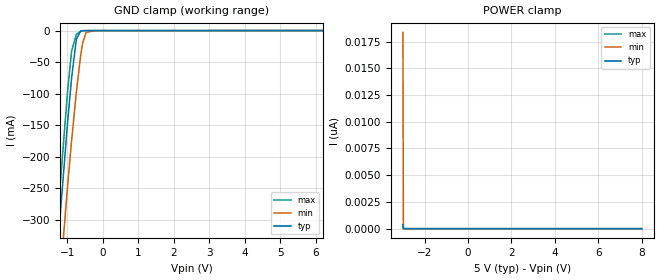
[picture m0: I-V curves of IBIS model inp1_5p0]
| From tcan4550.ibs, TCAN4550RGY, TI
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|   inp1_5p0 Model
[Model]   inp1_5p0
Model_type   Input
Vinl = 1.5
Vinh = 3.5
|   typ   min   max
C_comp   4.717pF   4.443pF   4.894pF
|  Where Nom  PVT is Nominal Process, 5V,   27C
|   Fast PVT is Strong Process,  5.25, -40C
|   Slow PVT is Weak Process,   4.75V, 150C
[Model spec]
|subparameter
Vinl   1.5   1.425   1.575
Vinh   3.5   3.325   3.675
[Voltage Range]   5   4.75   5.25
|Junction Temperature
[Temperature Range]   27   150   -40
[Power Clamp Reference]   5   4.75   5.25
[GND Clamp Reference]   0   0   0
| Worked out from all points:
|   GND clamp passes 1 mA (typ) near -0.63 V on its own axis
[GND Clamp]
|   Voltage   I(typ)   I(min)   I(max)
-3V       -1.774A    -1.806A    -1.769A
-1.526V   -547.9mA   -635.7mA   -506.4mA
-1.251V   -331.4mA   -428.8mA   -283.7mA
-1.218V   -306.4mA   -404.7mA   -258.2mA
-987mV    -143mA     -243.8mA   -93.65mA
-877mV    -74.98mA   -174.1mA   -32.25mA
-745mV    -14.11mA   -98.27mA   -6.274mA
-624mV    -794.5uA   -40.13mA   -894.3uA
-569mV    -217.7uA   -20.52mA   -257.7uA
-470mV    -33.98uA   -2.998mA   -37.08uA
-239mV    -18.51uA   -23.35uA   -22.76uA
8V        0A         0A         0A
[POWER Clamp]
|   Voltage   I(typ)   I(min)   I(max)
-3V       381.8pA    18.36nA    380.5pA
-2.978V   0A         0A         0A
-2.967V   0A         0A         0A
8V        0A         0A         0A
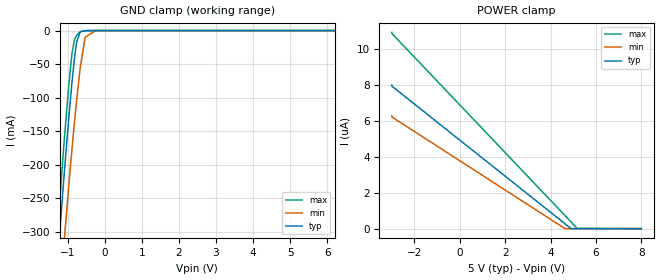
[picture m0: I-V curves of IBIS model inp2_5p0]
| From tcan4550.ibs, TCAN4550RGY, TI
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|   inp2_5p0 Model
[Model]   inp2_5p0
Model_type   Input
Vinl = 1.5
Vinh = 3.5
|   typ   min   max
C_comp   4.717pF   4.443pF   4.894pF
|  Where Nom  PVT is Nominal Process, 5V,   27C
|   Fast PVT is Strong Process,  5.25, -40C
|   Slow PVT is Weak Process,   4.75V, 150C
[Model spec]
|subparameter
Vinl   1.5   1.425   1.575
Vinh   3.5   3.325   3.675
[Voltage Range]   5   4.75   5.25
|Junction Temperature
[Temperature Range]   27   150   -40
[Power Clamp Reference]   5   4.75   5.25
[GND Clamp Reference]   0   0   0
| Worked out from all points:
|   GND clamp passes 1 mA (typ) near -0.63 V on its own axis
[GND Clamp]
|   Voltage   I(typ)   I(min)   I(max)
-3V       -1.774A    -1.806A    -1.769A
-1.35V    -407.9mA   -502.2mA   -362.1mA
-1.24V    -323mA     -420.7mA   -275.1mA
-1.097V   -218mA     -318.4mA   -168.5mA
-965mV    -128.8mA   -229.4mA   -79.78mA
-877mV    -74.98mA   -174.1mA   -32.25mA
-811mV    -39.84mA   -135mA     -13.29mA
-756mV    -17.43mA   -104.2mA   -7.114mA
-657mV    -1.761mA   -54.39mA   -1.703mA
-525mV    -65.42uA   -9.811mA   -72.23uA
-239mV    -137.8nA   -6.811uA   -213.8nA
8V        0A         0A         0A
[POWER Clamp]
|   Voltage   I(typ)   I(min)   I(max)
-3V       7.98uA     6.269uA    10.9uA
-2.989V   7.907uA    6.199uA    10.83uA
4.634V    277.2nA    2.624nA    731.9nA
4.898V    7.32nA     0A         379.5nA
5.173V    0A         0A         10.05nA
8V        0A         0A         0A
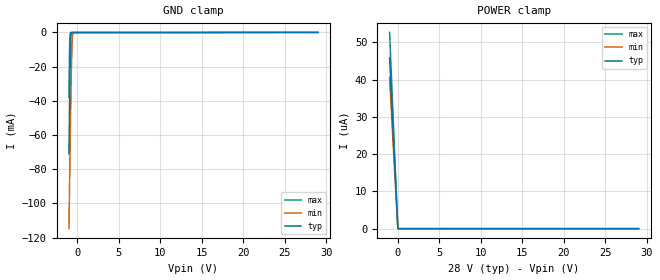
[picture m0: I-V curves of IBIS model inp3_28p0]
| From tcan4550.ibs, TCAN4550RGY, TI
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|   inp3_28p0 Model
[Model]   inp3_28p0
Model_type   Input
Vinl = 25
Vinh = 26
|   typ   min   max
C_comp   2.294pF   2.258pF   2.300pF
|  Where Nom  PVT is Nominal Process, 28V,   27C
|   Fast PVT is Strong Process,  26V, -40C
|   Slow PVT is Weak Process,   30V, 150C
[Model spec]
|subparameter
Vinl   25   23   27
Vinh   26   24   28
[Voltage Range]   28   26   30
|Junction Temperature
[Temperature Range]   27   150   -40
[Power Clamp Reference]   28   26   30
[GND Clamp Reference]   0   0   0
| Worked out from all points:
|   GND clamp passes 1 mA (typ) near -0.76 V on its own axis
[GND Clamp]
|   Voltage   I(typ)   I(min)   I(max)
-1V       -71.04mA   -114.8mA   -38.01mA
-940mV    -45.59mA   -93.27mA   -13.67mA
-910mV    -33.71mA   -82.69mA   -5.733mA
-880mV    -22.92mA   -72.29mA   -1.793mA
-850mV    -13.79mA   -62.13mA   -490.1uA
-820mV    -7.017mA   -52.27mA   -152.6uA
-790mV    -2.959mA   -42.82mA   -71.11uA
-730mV    -386.4uA   -25.67mA   -44.73uA
-640mV    -44.4uA    -7.393mA   -38.46uA
-580mV    -31.14uA   -2.071mA   -35.18uA
-490mV    -25.75uA   -223.3uA   -30.33uA
29V       0A         0A         0A
[POWER Clamp]
|   Voltage   I(typ)   I(min)   I(max)
-1V       45.82uA    40.47uA    52.66uA
-520mV    23.32uA    20.54uA    26.8uA
-100mV    4.244uA    3.751uA    4.87uA
-10mV     303.2nA    268.7nA    360.4nA
50mV      0A         0A         0A
29V       0A         0A         0A
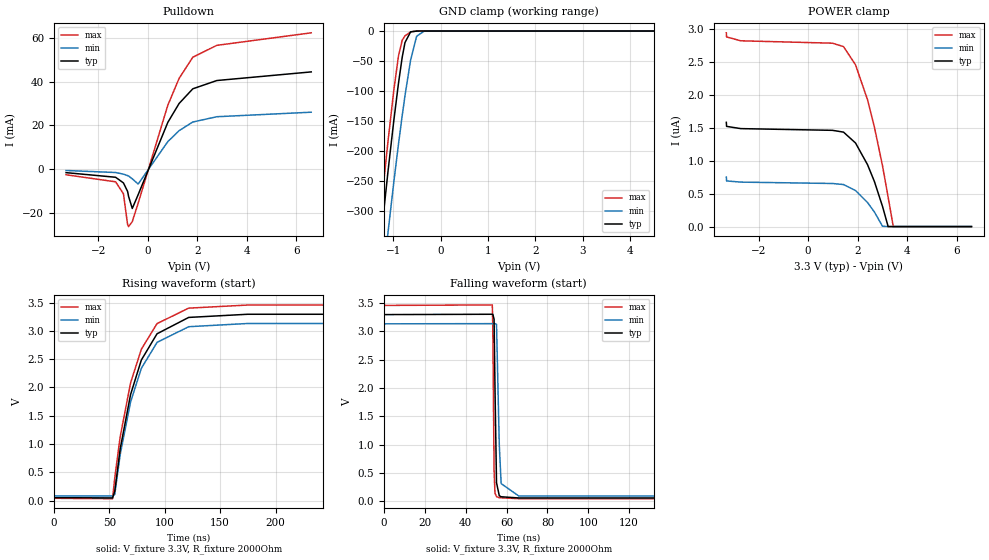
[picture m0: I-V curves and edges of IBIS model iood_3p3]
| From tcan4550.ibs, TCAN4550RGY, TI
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|   iood_3p3 Model
[Model]   iood_3p3
Model_type   I/O_open_drain
Polarity   Inverting
Enable   Active-High
Vinl = 0.99
Vinh = 2.31
Vmeas = 1.65
Vref = 3.3
Cref = 2pF
Rref = 2000
|   typ   min   max
C_comp   5.416pF   5.196pF   5.542pF
|  Where Nom  PVT is Nominal Process, 3.3V,   27C
|   Fast PVT is Strong Process,  3.465, -40C
|   Slow PVT is Weak Process,   3.135V, 150C
[Model spec]
|subparameter
Vinl   0.99   0.9405   1.0395
Vinh   2.31   2.1945   2.4255
[Voltage Range]   3.3   3.135   3.465
|Junction Temperature
[Temperature Range]   27   150   -40
[Pullup Reference]   3.3   3.135   3.465
[Pulldown Reference]   0   0   0
[Power Clamp Reference]   3.3   3.135   3.465
[GND Clamp Reference]   0   0   0
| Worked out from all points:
|   slope of the pulldown table from 0 to 0.495 V, typ, clamps not added: 35.6 ohm
|   GND clamp passes 1 mA (typ) near -0.62 V on its own axis
|   falling waveform, V_fixture 3.3V, R_fixture 2000Ohm: 20-80 % time 639ps typ, 1.06ns min, 470ps max; typ from 3.3 V to 0.053 V
|   rising waveform, V_fixture 3.3V, R_fixture 2000Ohm: 20-80 % time 24.4ns typ, 24.4ns min, 24.3ns max; typ from 0.053 V to 3.3 V
[Pulldown]
|   Voltage   I(typ)   I(min)   I(max)
-3.3V     -1.646mA   -663.5uA   -2.612mA
-1.3V     -3.761mA   -1.587mA   -5.841mA
-983.4mV  -6.351mA   -2.34mA    -11.31mA
-815.1mV  -10.26mA   -3.007mA   -25.49mA
-775.5mV  -12.54mA   -3.204mA   -26.33mA
-627mV    -18.04mA   -4.459mA   -24.06mA
-389.4mV  -11.73mA   -6.863mA   -15.61mA
808.5mV   21.35mA    12.55mA    29.21mA
1.264V    30mA       17.56mA    41.48mA
1.818V    36.72mA    21.53mA    51.17mA
2.788V    40.5mA     23.94mA    56.6mA
6.6V      44.45mA    26.01mA    62.33mA
[GND Clamp]
|   Voltage   I(typ)   I(min)   I(max)
-3.3V     -2.034A    -2.058A    -2.034A
-1.31V    -380.2mA   -477.5mA   -332.6mA
-1.251V   -334.5mA   -433.5mA   -285.9mA
-1.112V   -231.9mA   -333.7mA   -181.8mA
-993.3mV  -150.2mA   -252.6mA   -99.87mA
-894.3mV  -87.7mA    -189.1mA   -42.1mA
-815.1mV  -44.1mA    -141.4mA   -15.53mA
-755.7mV  -19.24mA   -107.8mA   -8.037mA
-636.9mV  -1.41mA    -48.49mA   -1.417mA
-508.2mV  -58.86uA   -8.59mA    -61.73uA
-349.8mV  -1.01uA    -208.4uA   -1.025uA
6.6V      0A         0A         0A
[POWER Clamp]
|   Voltage   I(typ)   I(min)   I(max)
-3.3V     1.58uA     751.3nA    2.937uA
-3.29V    1.519uA    691.9nA    2.875uA
-2.716V   1.485uA    674.2nA    2.816uA
986.7mV   1.459uA    653.3nA    2.78uA
1.432V    1.432uA    637.3nA    2.728uA
1.917V    1.267uA    546.3nA    2.452uA
2.402V    938.4nA    364.5nA    1.922uA
2.68V     682.9nA    221.1nA    1.507uA
3.006V    307.1nA    5.102nA    923.2nA
3.234V    548.8pA    0A         446.7nA
3.442V    0A         0A         0A
6.6V      0A         0A         0A
[Ramp]
R_load = 2000
|   typ   min   max
dV/dt_r   1.94618/2.44387e-08   1.82918/2.44445e-08   2.05049/2.4312e-08
dV/dt_f   1.94618/6.37173e-10   1.82918/1.06111e-09   2.05049/4.67593e-10
[Falling Waveform]
V_fixture = 3.3V
V_fixture_min = 3.135V
V_fixture_max = 3.465V
R_fixture = 2000Ohm
C_fixture = 0F
|   Time   V(typ)   V(min)   V(max)
0s        3.297V     3.134V     3.459V
53.03ns   3.303V     3.137V     3.468V
53.28ns   3.304V     3.137V     3.053V
53.9ns    3.214V     3.137V     545.6mV
54.34ns   2.004V     3.137V     138.2mV
55.09ns   324.7mV    3.124V     78.97mV
56.45ns   94.28mV    988.5mV    58.48mV
57.36ns   76.02mV    308.8mV    56.93mV
65.99ns   54.87mV    89.25mV    42.28mV
25us      53.31mV    84.92mV    41.81mV
[Rising Waveform]
V_fixture = 3.3V
V_fixture_min = 3.135V
V_fixture_max = 3.465V
R_fixture = 2000Ohm
C_fixture = 0F
|   Time   V(typ)   V(min)   V(max)
0s        53.31mV    84.92mV    41.81mV
52.97ns   48.32mV    83.65mV    34.96mV
54.95ns   168.9mV    110.2mV    403.2mV
59.86ns   916.1mV    815mV      1.131V
69.21ns   1.875V     1.743V     2.081V
78.92ns   2.485V     2.338V     2.675V
93.07ns   2.949V     2.797V     3.129V
121.6ns   3.238V     3.074V     3.402V
174.8ns   3.294V     3.131V     3.457V
25us      3.297V     3.134V     3.459V
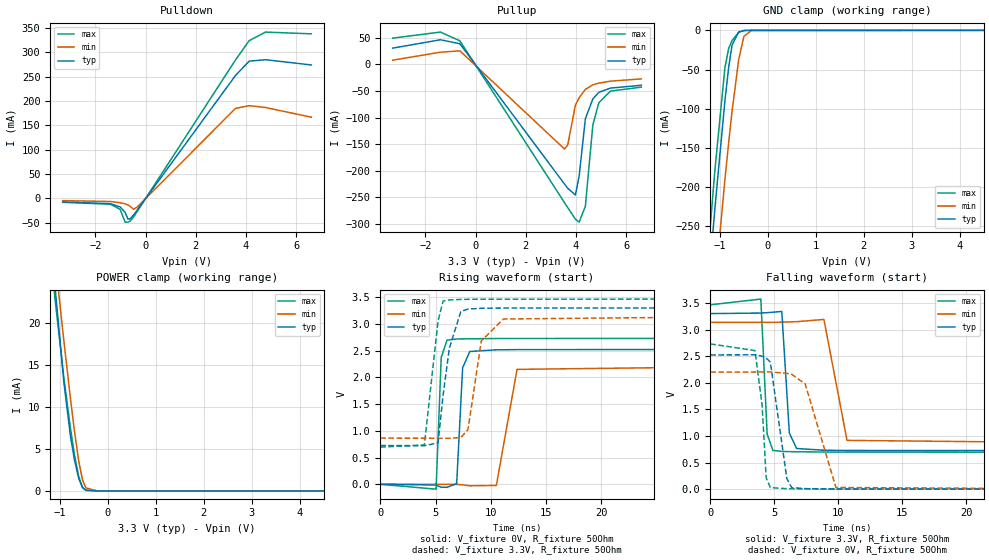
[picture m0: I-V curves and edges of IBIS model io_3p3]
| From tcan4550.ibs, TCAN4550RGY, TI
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|   io_3p3 Model
[Model]   io_3p3
Model_type   I/O
Polarity   Non-Inverting
Enable   Active-High
Vinl = 0.99
Vinh = 2.31
Vmeas = 1.65
Vref = 0
Cref = 2pF
Rref = 100000
|   typ   min   max
C_comp   9.675pF   8.583pF   10.03pF
|  Where Nom  PVT is Nominal Process, 3.3V,   27C
|   Fast PVT is Strong Process,  3.465, -40C
|   Slow PVT is Weak Process,   3.135V, 150C
[Model spec]
|subparameter
Vinl   0.99   0.9405   1.0395
Vinh   2.31   2.1945   2.4255
[Voltage Range]   3.3   3.135   3.465
|Junction Temperature
[Temperature Range]   27   150   -40
[Pullup Reference]   3.3   3.135   3.465
[Pulldown Reference]   0   0   0
[Power Clamp Reference]   3.3   3.135   3.465
[GND Clamp Reference]   0   0   0
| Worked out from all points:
|   slope of the pulldown table from 0 to 0.495 V, typ, clamps not added: 14.1 ohm
|   slope of the pullup table from 0 to 0.495 V, typ, clamps not added: 15.4 ohm
|   GND clamp passes 1 mA (typ) near -0.57 V on its own axis
|   POWER clamp passes 1 mA (typ) near -0.58 V on its own axis
|   falling waveform, V_fixture 3.3V, R_fixture 50Ohm: 20-80 % time 335ps typ, 504ps min, 257ps max; typ from 3.3 V to 0.724 V
|   rising waveform, V_fixture 0V, R_fixture 50Ohm: 20-80 % time 307ps typ, 501ps min, 221ps max; typ from 0 V to 2.52 V
|   rising waveform, V_fixture 3.3V, R_fixture 50Ohm: 20-80 % time 1.04ns typ, 1ns min, 953ps max; typ from 0.724 V to 3.3 V
|   falling waveform, V_fixture 0V, R_fixture 50Ohm: 20-80 % time 819ps typ, 1.35ns min, 508ps max; typ from 2.52 V to 0 V
[Pulldown]
|   Voltage   I(typ)   I(min)   I(max)
-3.3V     -7.321mA   -4.376mA   -7.77mA
-1.399V   -10.65mA   -6.17mA    -11.81mA
-1.013V   -17.43mA   -8.661mA   -22.41mA
-815.1mV  -28.61mA   -11.12mA   -48.5mA
-706.2mV  -41.98mA   -13.18mA   -48.68mA
-617.1mV  -41.78mA   -16.24mA   -46.47mA
-478.5mV  -33.95mA   -22.1mA    -38.04mA
-339.9mV  -24.21mA   -17.84mA   -27.11mA
3.58V     252.5mA    184.9mA    284.3mA
4.125V    281.9mA    190.6mA    324mA
4.778V    284.9mA    186.7mA    341.6mA
6.6V      274.1mA    166.9mA    338mA
[GND Clamp]
|   Voltage   I(typ)   I(min)   I(max)
-3.3V     -2.035A    -2.059A    -2.036A
-1.32V    -389.2mA   -485.8mA   -342.9mA
-1.251V   -335.9mA   -434.5mA   -288.4mA
-1.122V   -240.6mA   -341.7mA   -192mA
-1.092V   -219.5mA   -320.9mA   -170.8mA
-894.3mV  -89.68mA   -190.1mA   -47.42mA
-815.1mV  -46.35mA   -142.4mA   -22.67mA
-745.8mV  -18.8mA    -103.3mA   -13.02mA
-607.2mV  -2.033mA   -37.01mA   -2.543mA
-498.3mV  -237.2uA   -7.541mA   -248.7uA
-339.9mV  -14.59uA   -195.7uA   -15.4uA
6.6V      0A         0A         0A
[Pullup]
|   Voltage   I(typ)   I(min)   I(max)
-3.3V     30.66mA    7.971mA    49.52mA
-1.399V   46.39mA    22.94mA    60.85mA
-627mV    38.96mA    25.59mA    44.46mA
3.541V    -225.2mA   -159.3mA   -260.2mA
3.67V     -233.1mA   -151.6mA   -269.6mA
3.977V    -245.8mA   -76.26mA   -291.4mA
4.125V    -209.8mA   -62.46mA   -297mA
4.372V    -102.3mA   -47.06mA   -266.8mA
4.67V     -65mA      -38.41mA   -113.9mA
4.907V    -52.56mA   -35.12mA   -72.35mA
5.372V    -44.59mA   -31.58mA   -50.2mA
6.6V      -39.25mA   -27.21mA   -42.81mA
[POWER Clamp]
|   Voltage   I(typ)   I(min)   I(max)
-3.3V     185.2mA    152.1mA    196.5mA
-1.191V   30.4mA     32.54mA    28.48mA
-1.142V   27.04mA    29.85mA    25.32mA
-1.102V   24.4mA     27.71mA    22.96mA
-914.1mV  12.81mA    17.76mA    13.36mA
-775.5mV  6.381mA    10.82mA    7.329mA
-696.3mV  3.709mA    7.153mA    4.35mA
-607.2mV  1.498mA    3.57mA     1.717mA
-528mV    410.4uA    1.31mA     405.8uA
-458.7mV  84.75uA    360.7uA    61.26uA
-211.2mV  0A         963.1nA    0A
6.6V      0A         0A         0A
[Ramp]
R_load = 50
|   typ   min   max
dV/dt_r   1.51305/3.05831e-10   1.31974/4.99333e-10   1.63771/2.20599e-10
dV/dt_f   1.54536/3.33578e-10   1.36296/5.00669e-10   1.66199/2.55608e-10
[Falling Waveform]
V_fixture = 3.3V
V_fixture_min = 3.135V
V_fixture_max = 3.465V
R_fixture = 50Ohm
C_fixture = 0F
|   Time   V(typ)   V(min)   V(max)
0s        3.3V       3.135V     3.465V
3.953ns   3.31V      3.135V     3.573V
4.447ns   3.317V     3.135V     1.034V
4.893ns   3.326V     3.135V     729.6mV
5.59ns    3.34V      3.139V     709.4mV
6.182ns   1.054V     3.144V     705.3mV
6.751ns   764.5mV    3.148V     703.2mV
8.883ns   731.9mV    3.19V      697.7mV
10.69ns   727.5mV    917.2mV    697.5mV
33ns      724.4mV    863.4mV    695mV
[Rising Waveform]
V_fixture = 0V
V_fixture_min = 0V
V_fixture_max = 0V
R_fixture = 50Ohm
C_fixture = 0F
|   Time   V(typ)   V(min)   V(max)
0s        109.1uV    131.5uV    119.9uV
5.052ns   -13.65mV   283.3uV    -91.42mV
5.518ns   -55.33mV   297.3uV    2.374V
6.04ns    -57.27mV   313uV      2.696V
6.917ns   12.08mV    -2.397mV   2.718V
7.456ns   2.179V     -10.8mV    2.72V
8.107ns   2.484V     -28.63mV   2.722V
10.51ns   2.516V     -21.63mV   2.727V
12.38ns   2.519V     2.15V      2.727V
33ns      2.522V     2.2V       2.73V
[Rising Waveform]
V_fixture = 3.3V
V_fixture_min = 3.135V
V_fixture_max = 3.465V
R_fixture = 50Ohm
C_fixture = 0F
|   Time   V(typ)   V(min)   V(max)
0s        724.4mV    863.4mV    695mV
3.991ns   721.5mV    862mV      735.1mV
5.232ns   776mV      861.5mV    3.058V
5.692ns   1.677V     861.3mV    3.428V
6.256ns   2.546V     861.1mV    3.449V
7.296ns   3.233V     875mV      3.458V
7.942ns   3.277V     1.025V     3.46V
9.145ns   3.293V     2.682V     3.462V
11.15ns   3.297V     3.092V     3.462V
33ns      3.3V       3.135V     3.465V
[Falling Waveform]
|Gnd
V_fixture = 0V
V_fixture_min = 0V
V_fixture_max = 0V
R_fixture = 50Ohm
C_fixture = 0F
|   Time   V(typ)   V(min)   V(max)
0s        2.522V     2.2V       2.73V
3.494ns   2.526V     2.202V     2.605V
4.053ns   2.499V     2.203V     1.58V
4.37ns    2.465V     2.203V     215.5mV
4.695ns   2.388V     2.203V     29.02mV
5.988ns   196.1mV    2.177V     8.705mV
6.362ns   29.12mV    2.159V     7.721mV
7.42ns    9.64mV     1.978V     4.939mV
9.821ns   2.743mV    31.65mV    2.475mV
33ns      109.1uV    131.5uV    119.8uV
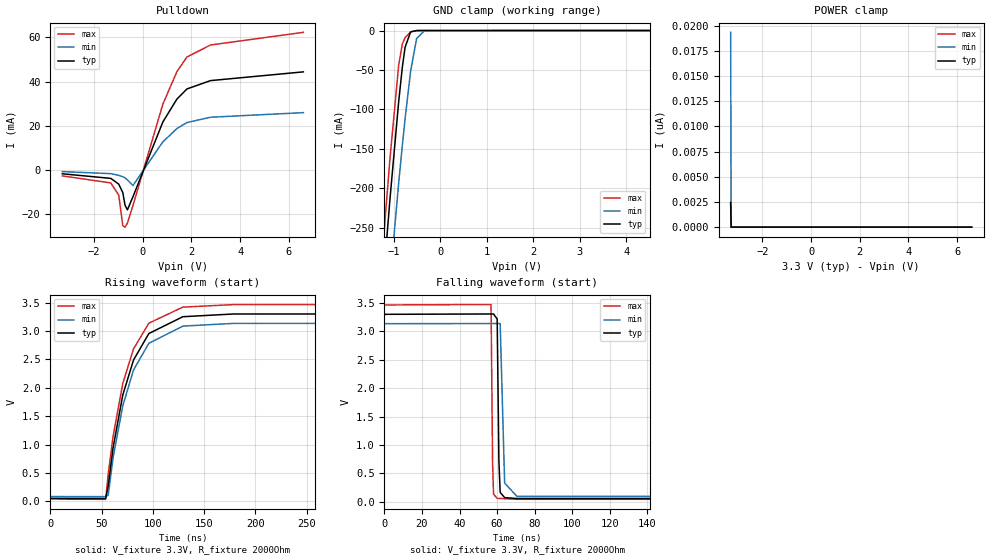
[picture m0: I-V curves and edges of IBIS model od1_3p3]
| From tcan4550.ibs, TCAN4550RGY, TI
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|   od1_3p3 Model
[Model]   od1_3p3
Model_type   Open_drain
Polarity   Non-Inverting
Vmeas = 1.8
Vref = 3.3
Cref = 2pF
Rref = 2000
|   typ   min   max
C_comp   6.076pF   5.776pF   6.275pF
|  Where Nom  PVT is Nominal Process, 3.3V,   27C
|   Fast PVT is Strong Process,  3.465, -40C
|   Slow PVT is Weak Process,   3.135V, 150C
[Voltage Range]   3.3   3.135   3.465
|Junction Temperature
[Temperature Range]   27   150   -40
[Pullup Reference]   3.3   3.135   3.465
[Pulldown Reference]   0   0   0
[Power Clamp Reference]   3.3   3.135   3.465
[GND Clamp Reference]   0   0   0
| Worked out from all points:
|   slope of the pulldown table from 0 to 0.495 V, typ, clamps not added: 35.6 ohm
|   GND clamp passes 1 mA (typ) near -0.61 V on its own axis
|   falling waveform, V_fixture 3.3V, R_fixture 2000Ohm: 20-80 % time 663ps typ, 1.1ns min, 484ps max; typ from 3.3 V to 0.053 V
|   rising waveform, V_fixture 3.3V, R_fixture 2000Ohm: 20-80 % time 25.7ns typ, 25.9ns min, 25.4ns max; typ from 0.053 V to 3.3 V
[Pulldown]
|   Voltage   I(typ)   I(min)   I(max)
-3.3V     -1.642mA   -661.3uA   -2.594mA
-1.31V    -3.716mA   -1.573mA   -5.761mA
-983.4mV  -6.305mA   -2.335mA   -11.27mA
-815.1mV  -10.18mA   -2.98mA    -25.16mA
-726mV    -15.79mA   -3.464mA   -25.77mA
-627mV    -17.95mA   -4.409mA   -23.98mA
-399.3mV  -12.02mA   -6.941mA   -15.99mA
828.3mV   21.78mA    12.8mA     29.81mA
1.403V    32.09mA    18.78mA    44.48mA
1.818V    36.72mA    21.53mA    51.17mA
2.788V    40.5mA     23.94mA    56.6mA
6.6V      44.45mA    26.01mA    62.33mA
[GND Clamp]
|   Voltage   I(typ)   I(min)   I(max)
-3.3V     -2.041A    -2.068A    -2.039A
-1.32V    -391.2mA   -489.8mA   -343mA
-1.261V   -345.3mA   -445.7mA   -296mA
-1.181V   -285.6mA   -387.8mA   -235.2mA
-1.082V   -214mA     -317.6mA   -162.8mA
-894.3mV  -90.23mA   -193.3mA   -44.01mA
-815.1mV  -46.29mA   -145.3mA   -16.98mA
-755.7mV  -21.04mA   -111.4mA   -8.93mA
-636.9mV  -1.733mA   -51.32mA   -1.669mA
-508.2mV  -73.77uA   -10.07mA   -76.19uA
-339.9mV  -448.5nA   -216uA     -95.85nA
6.6V      0A         0A         0A
[POWER Clamp]
|   Voltage   I(typ)   I(min)   I(max)
-3.3V     2.437nA    19.35nA    2.483nA
-3.28V    0A         0A         0A
-3.27V    0A         0A         0A
6.6V      0A         0A         0A
[Ramp]
R_load = 2000
|   typ   min   max
dV/dt_r   1.94801/2.57448e-08   1.83003/2.59238e-08   2.05391/2.53975e-08
dV/dt_f   1.94801/6.60595e-10   1.83003/1.10044e-09   2.05391/4.83347e-10
[Falling Waveform]
V_fixture = 3.3V
V_fixture_min = 3.135V
V_fixture_max = 3.465V
R_fixture = 2000Ohm
C_fixture = 0F
|   Time   V(typ)   V(min)   V(max)
0s        3.3V       3.135V     3.465V
56.79ns   3.306V     3.138V     3.473V
57.62ns   3.306V     3.138V     675.2mV
58.13ns   3.306V     3.138V     132mV
60.06ns   3.217V     3.138V     59.59mV
60.97ns   731.4mV    3.138V     58.09mV
61.66ns   164.2mV    3.137V     56.96mV
64.04ns   71.56mV    327.3mV    53.05mV
70.63ns   56.3mV     93.43mV    42.19mV
25us      53.31mV    84.92mV    41.81mV
[Rising Waveform]
V_fixture = 3.3V
V_fixture_min = 3.135V
V_fixture_max = 3.465V
R_fixture = 2000Ohm
C_fixture = 0F
|   Time   V(typ)   V(min)   V(max)
0s        53.31mV    84.92mV    41.81mV
53.97ns   49.46mV    83.5mV     36.18mV
56.49ns   274.3mV    111.8mV    483.6mV
61.19ns   943.2mV    766.3mV    1.144V
70.63ns   1.87V      1.68V      2.073V
81.11ns   2.487V     2.312V     2.683V
96.06ns   2.954V     2.782V     3.136V
129.2ns   3.25V      3.085V     3.419V
178.5ns   3.298V     3.132V     3.463V
25us      3.3V       3.135V     3.465V
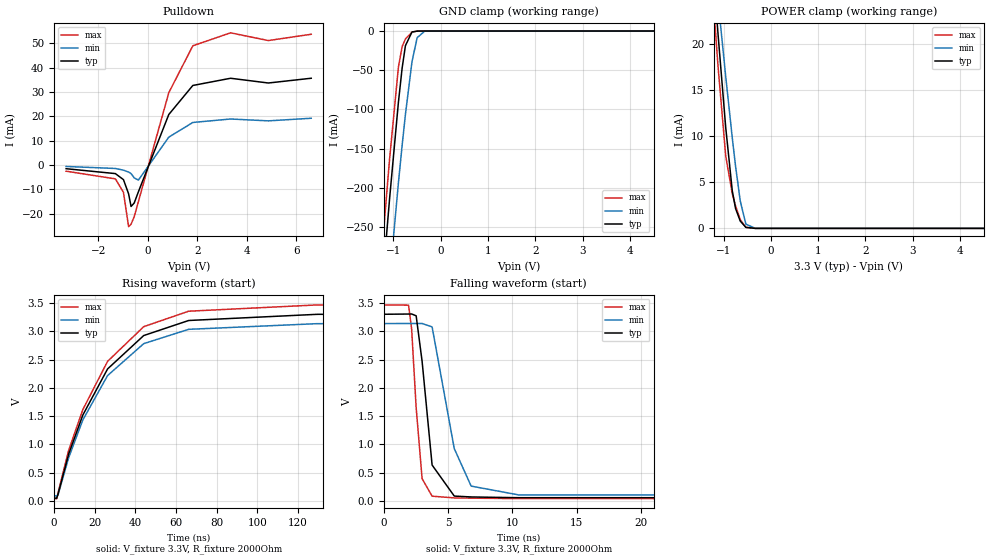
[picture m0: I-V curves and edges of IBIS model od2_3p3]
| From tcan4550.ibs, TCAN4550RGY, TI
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|   od2_3p3 Model
[Model]   od2_3p3
Model_type   Open_drain
Polarity   Non-Inverting
Vmeas = 1.65
Vref = 3.3
Cref = 2pF
Rref = 2000
|   typ   min   max
C_comp   6.945pF   6.601pF   7.074pF
|  Where Nom  PVT is Nominal Process, 3.3V,   27C
|   Fast PVT is Strong Process,  3.465, -40C
|   Slow PVT is Weak Process,   3.135V, 150C
[Voltage Range]   3.3   3.135   3.465
|Junction Temperature
[Temperature Range]   27   150   -40
[Pullup Reference]   3.3   3.135   3.465
[Pulldown Reference]   0   0   0
[Power Clamp Reference]   3.3   3.135   3.465
[GND Clamp Reference]   0   0   0
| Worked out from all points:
|   slope of the pulldown table from 0 to 0.495 V, typ, clamps not added: 37.6 ohm
|   GND clamp passes 1 mA (typ) near -0.60 V on its own axis
|   POWER clamp passes 1 mA (typ) near -0.67 V on its own axis
|   falling waveform, V_fixture 3.3V, R_fixture 2000Ohm: 20-80 % time 802ps typ, 1.41ns min, 554ps max; typ from 3.3 V to 0.056 V
|   rising waveform, V_fixture 3.3V, R_fixture 2000Ohm: 20-80 % time 27.9ns typ, 27.6ns min, 27.8ns max; typ from 0.056 V to 3.3 V
[Pulldown]
|   Voltage   I(typ)   I(min)   I(max)
-3.3V     -1.508mA   -587.1uA   -2.527mA
-1.31V    -3.52mA    -1.413mA   -5.682mA
-983.4mV  -5.988mA   -2.116mA   -11.19mA
-775.5mV  -11.83mA   -2.884mA   -25.29mA
-676.5mV  -17.02mA   -3.508mA   -24.32mA
-547.8mV  -15.57mA   -5.288mA   -21.21mA
-379.5mV  -10.98mA   -6.186mA   -15.01mA
848.1mV   20.77mA    11.46mA    29.72mA
1.818V    32.69mA    17.49mA    48.99mA
3.343V    35.65mA    18.91mA    54.32mA
4.867V    33.7mA     18.15mA    51.14mA
6.6V      35.66mA    19.22mA    53.73mA
[GND Clamp]
|   Voltage   I(typ)   I(min)   I(max)
-3.3V     -2.041A    -2.068A    -2.04A
-1.32V    -391.8mA   -490.3mA   -343.8mA
-1.261V   -345.9mA   -446.1mA   -297mA
-1.181V   -286.2mA   -388.3mA   -236.3mA
-1.082V   -214.7mA   -318.1mA   -164mA
-894.3mV  -90.91mA   -193.7mA   -46.02mA
-815.1mV  -47.02mA   -145.7mA   -19.73mA
-745.8mV  -18.66mA   -106.2mA   -10.19mA
-607.2mV  -1.204mA   -39.07mA   -1.422mA
-498.3mV  -95.57uA   -8.536mA   -97.45uA
-339.9mV  -898.9nA   -220.9uA   -241.7nA
6.6V      0A         0A         0A
[POWER Clamp]
|   Voltage   I(typ)   I(min)   I(max)
-3.3V     177.5mA    145.6mA    188.6mA
-1.27V    31.44mA    32.88mA    28.68mA
-1.201V   26.74mA    29.21mA    23.62mA
-1.132V   22.13mA    25.58mA    18.7mA
-1.112V   20.83mA    24.56mA    17.34mA
-953.7mV  10.95mA    16.49mA    7.865mA
-815.1mV  4.078mA    9.826mA    3.762mA
-745.8mV  2.162mA    6.753mA    2.431mA
-646.8mV  795.4uA    2.984mA    959.7uA
-528mV    111.9uA    465uA      111.1uA
-330mV    493.8nA    4.833uA    72.61nA
6.6V      0A         0A         0A
[Ramp]
R_load = 2000
|   typ   min   max
dV/dt_r   1.94661/2.79443e-08   1.82529/2.75668e-08   2.05357/2.78216e-08
dV/dt_f   1.94661/8.01238e-10   1.82529/1.41044e-09   2.05357/5.54202e-10
[Falling Waveform]
V_fixture = 3.3V
V_fixture_min = 3.135V
V_fixture_max = 3.465V
R_fixture = 2000Ohm
C_fixture = 0F
|   Time   V(typ)   V(min)   V(max)
0s        3.3V       3.135V     3.465V
1.916ns   3.304V     3.137V     3.461V
2.157ns   3.305V     3.137V     3.037V
2.508ns   3.273V     3.137V     1.651V
2.972ns   2.467V     3.137V     395.9mV
3.75ns    636.9mV    3.077V     86.93mV
5.475ns   88.81mV    927.7mV    56.34mV
6.79ns    73.04mV    264.9mV    51.78mV
10.5ns    59.8mV     108.7mV    44.38mV
500ns     55.64mV    92.82mV    42.38mV
[Rising Waveform]
V_fixture = 3.3V
V_fixture_min = 3.135V
V_fixture_max = 3.465V
R_fixture = 2000Ohm
C_fixture = 0F
|   Time   V(typ)   V(min)   V(max)
0s        55.64mV    92.82mV    42.38mV
1.43ns    51.24mV    90.88mV    42.46mV
2.06ns    121.4mV    107.8mV    145.3mV
7.308ns   831.9mV    768.4mV    898.5mV
14.26ns   1.52V      1.434V     1.616V
26.42ns   2.334V     2.217V     2.468V
44.18ns   2.924V     2.781V     3.081V
66.28ns   3.19V      3.034V     3.354V
129.4ns   3.299V     3.134V     3.465V
500ns     3.3V       3.135V     3.465V
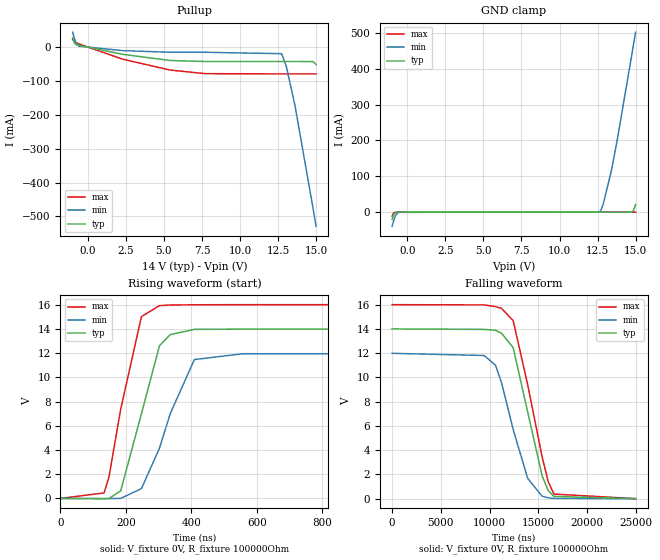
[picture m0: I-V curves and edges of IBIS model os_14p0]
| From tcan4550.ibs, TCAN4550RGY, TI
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|   os_14p0 Model
[Model]   os_14p0
Model_type   Open_source
Polarity   Non-Inverting
Vmeas = 7
Vref = 0
Cref = 2pF
Rref = 100000
|   typ   min   max
C_comp   1.635pF   1.569pF   1.697pF
|  Where Nom  PVT is Nominal Process, 14V,   27C
|   Fast PVT is Strong Process,  16V, -40C
|   Slow PVT is Weak Process,   12V, 150C
[Voltage Range]   14   12   16
|Junction Temperature
[Temperature Range]   27   150   -40
[Pullup Reference]   14   12   16
[Pulldown Reference]   0   0   0
[Power Clamp Reference]   14   12   16
[GND Clamp Reference]   0   0   0
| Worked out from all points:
|   slope of the pullup table from 0 to 2.1 V, typ, clamps not added: 110 ohm
|   GND clamp passes 1 mA (typ) near -0.80 V on its own axis
|   falling waveform, V_fixture 0V, R_fixture 100000Ohm: 20-80 % time 2.26us typ, 2.36us min, 2.44us max; typ from 14 V to 0 V
|   rising waveform, V_fixture 0V, R_fixture 100000Ohm: 20-80 % time 74.2ns typ, 88.6ns min, 65.7ns max; typ from 0 V to 14 V
[GND Clamp]
|   Voltage   I(typ)   I(min)   I(max)
-1V       -20.26mA   -39.39mA   -11.19mA
-904mV    -7.66mA    -24.46mA   -2.053mA
-792mV    -785.4uA   -10.53mA   -274.7uA
-600mV    -3.378uA   -460.6uA   -4.372uA
12.6V     27.37nA    511.2uA    25.4nA
12.71V    27.52nA    4.535mA    25.42nA
12.87V    27.76nA    21.71mA    25.46nA
13.42V    29.1nA     117.3mA    25.64nA
13.8V     31.24nA    202.7mA    25.84nA
14.76V    287.2uA    440.9mA    26.75nA
14.87V    5.059mA    469.1mA    26.92nA
15V       21.31mA    501.4mA    27.14nA
[Pullup]
|   Voltage   I(typ)   I(min)   I(max)
-1V       28mA       44.49mA    23.8mA
-872mV    12.47mA    24.67mA    15.24mA
-776mV    8.269mA    12.92mA    13.46mA
-600mV    6.175mA    3.451mA    10.35mA
2.28V     -20.66mA   -9.718mA   -34.95mA
5.384V    -38.88mA   -14.59mA   -67.05mA
7.704V    -41.92mA   -14.61mA   -77.85mA
12.74V    -41.99mA   -18.79mA   -78.63mA
13.05V    -41.99mA   -57.64mA   -78.63mA
13.62V    -41.99mA   -173.7mA   -78.63mA
14.81V    -42.11mA   -478.5mA   -78.64mA
15V       -51.01mA   -529.4mA   -78.64mA
[Ramp]
R_load = 100000
|   typ   min   max
dV/dt_r   8.39152/7.41508e-08   7.1852/8.86055e-08   9.59423/6.56925e-08
dV/dt_f   8.39152/2.25771e-06   7.1852/2.3636e-06   9.59423/2.4398e-06
[Falling Waveform]
V_fixture = 0V
V_fixture_min = 0V
V_fixture_max = 0V
R_fixture = 100000Ohm
C_fixture = 0F
|   Time   V(typ)   V(min)   V(max)
0s        13.99V     11.98V     15.99V
9.439us   13.95V     11.8V      15.97V
10.61us   13.88V     11.01V     15.83V
11.23us   13.64V     9.575V     15.69V
12.43us   12.45V     5.704V     14.67V
13.92us   7.147V     1.674V     9.402V
15.4us    1.889V     207.5mV    3.465V
16.02us   680.3mV    72.59mV    1.412V
16.62us   187.5mV    22.45mV    380.7mV
25us      389uV      301.5uV    336.3uV
[Rising Waveform]
V_fixture = 0V
V_fixture_min = 0V
V_fixture_max = 0V
R_fixture = 100000Ohm
C_fixture = 0F
|   Time   V(typ)   V(min)   V(max)
0s        389uV      301.5uV    333.9uV
133.3ns   -17.92mV   -11.52mV   459.8mV
148.6ns   -1.332mV   -11.87mV   1.805V
184.2ns   634.5mV    6.821mV    7.374V
247.5ns   6.985V     814.3mV    15V
302.6ns   12.59V     4.139V     15.91V
335.4ns   13.52V     6.984V     15.96V
409.3ns   13.95V     11.46V     15.98V
557.6ns   13.97V     11.94V     15.99V
25us      13.99V     11.98V     15.99V
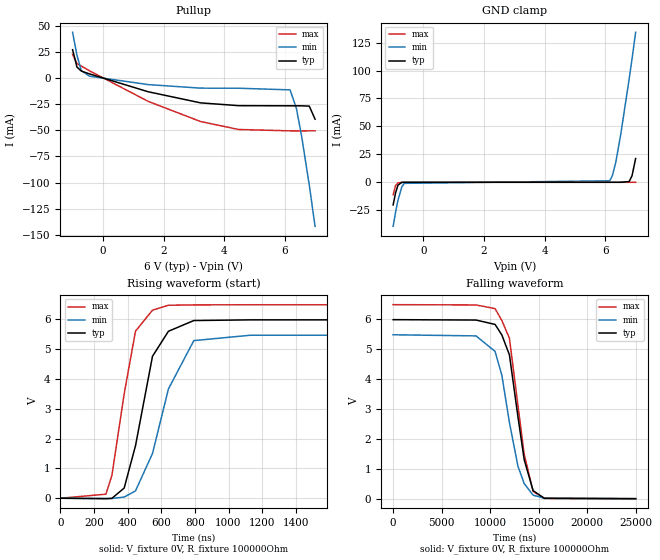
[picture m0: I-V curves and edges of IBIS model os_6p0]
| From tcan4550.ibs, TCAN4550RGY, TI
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|   os_6p0 Model
[Model]   os_6p0
Model_type   Open_source
Polarity   Non-Inverting
Vmeas = 3
Vref = 0
Cref = 2pF
Rref = 100000
|   typ   min   max
C_comp   2.117pF   2.059pF   2.166pF
|  Where Nom  PVT is Nominal Process, 6V,   27C
|   Fast PVT is Strong Process,  6.5V, -40C
|   Slow PVT is Weak Process,   5.5V, 150C
[Voltage Range]   6   5.5   6.5
|Junction Temperature
[Temperature Range]   27   150   -40
[Pullup Reference]   6   5.5   6.5
[Pulldown Reference]   0   0   0
[Power Clamp Reference]   6   5.5   6.5
[GND Clamp Reference]   0   0   0
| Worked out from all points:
|   slope of the pullup table from 0 to 0.9 V, typ, clamps not added: 112 ohm
|   GND clamp passes 1 mA (typ) near -0.80 V on its own axis
|   falling waveform, V_fixture 0V, R_fixture 100000Ohm: 20-80 % time 1.57us typ, 1.81us min, 1.53us max; typ from 5.99 V to 0 V
|   rising waveform, V_fixture 0V, R_fixture 100000Ohm: 20-80 % time 123ns typ, 152ns min, 104ns max; typ from 0 V to 5.99 V
[GND Clamp]
|   Voltage   I(typ)   I(min)   I(max)
-1V       -20.26mA   -39.39mA   -11.19mA
-920mV    -9.44mA    -26.92mA   -2.943mA
-840mV    -2.549mA   -16.04mA   -531uA
-712mV    -79.65uA   -4.001mA   -83.1uA
-632mV    -8.506uA   -945.4uA   -11.95uA
6.144V    22.25nA    1.339mA    17.83nA
6.232V    25.17nA    5.857mA    18.08nA
6.344V    27.86nA    17.77mA    18.58nA
6.504V    175.3nA    42.06mA    21.08nA
6.784V    612.1uA    91.92mA    25.7nA
6.88V     5.705mA    110.1mA    27.51nA
7V        21.23mA    134.2mA    115.9nA
[Pullup]
|   Voltage   I(typ)   I(min)   I(max)
-1V       27.51mA    44.18mA    23.12mA
-856mV    10.83mA    22.15mA    14.24mA
-712mV    6.971mA    7.343mA    11.77mA
-440mV    4.246mA    2.068mA    7.203mA
1.496V    -12.9mA    -6.02mA    -22.13mA
3.224V    -23.55mA   -9.419mA   -41.47mA
4.48V     -26.23mA   -9.506mA   -49.1mA
6.176V    -26.37mA   -11.09mA   -50.41mA
6.384V    -26.37mA   -28.85mA   -50.42mA
6.552V    -26.38mA   -54.71mA   -50.43mA
6.808V    -26.65mA   -102.3mA   -50.39mA
7V        -39.22mA   -142mA     -50.39mA
[Ramp]
R_load = 100000
|   typ   min   max
dV/dt_r   3.59609/1.23135e-07   3.29266/1.52012e-07   3.89751/1.04374e-07
dV/dt_f   3.59609/1.57182e-06   3.29266/1.81453e-06   3.89751/1.53061e-06
[Falling Waveform]
V_fixture = 0V
V_fixture_min = 0V
V_fixture_max = 0V
R_fixture = 100000Ohm
C_fixture = 0F
|   Time   V(typ)   V(min)   V(max)
0s        5.994V     5.488V     6.496V
8.548us   5.981V     5.45V      6.487V
10.51us   5.834V     4.931V     6.362V
11.21us   5.48V      4.126V     5.966V
11.99us   4.813V     2.55V      5.368V
12.87us   2.734V     1.084V     3.118V
13.51us   1.309V     507.3mV    1.487V
14.43us   269.8mV    116.6mV    243.6mV
15.59us   12.74mV    15.83mV    9.496mV
25us      235.3uV    236.1uV    170.2uV
[Rising Waveform]
V_fixture = 0V
V_fixture_min = 0V
V_fixture_max = 0V
R_fixture = 100000Ohm
C_fixture = 0F
|   Time   V(typ)   V(min)   V(max)
0s        235.3uV    236.1uV    173.1uV
270.4ns   -14.85mV   -9.034mV   136.2mV
306.1ns   -4.061mV   -7.029mV   764.4mV
379.2ns   342.9mV    39.67mV    3.505V
446.6ns   1.764V     247.4mV    5.608V
547.6ns   4.763V     1.501V     6.311V
642.4ns   5.603V     3.667V     6.476V
793.5ns   5.963V     5.29V      6.488V
1.13us    5.986V     5.47V      6.493V
25us      5.994V     5.488V     6.496V
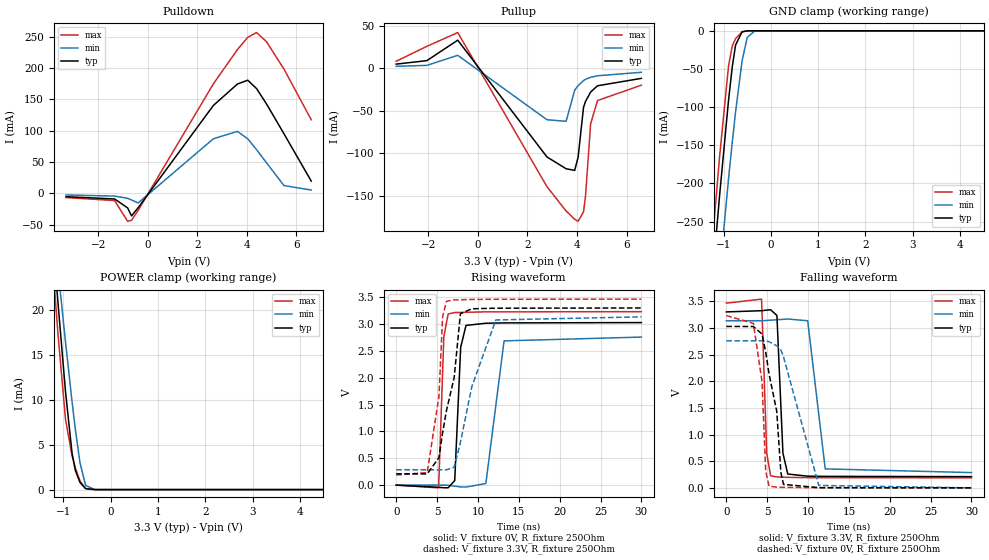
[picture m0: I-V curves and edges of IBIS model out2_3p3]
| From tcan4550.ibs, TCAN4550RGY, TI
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|   out2_3p3 Model
[Model]   out2_3p3
Model_type   3-state
Polarity   Non-Inverting
Vmeas = 1.65
Vref = 0
Cref = 2pF
Rref = 100000
|   typ   min   max
C_comp   6.944pF   6.601pF   7.074pF
|  Where Nom  PVT is Nominal Process, 3.3V,   27C
|   Fast PVT is Strong Process,  3.465, -40C
|   Slow PVT is Weak Process,   3.135V, 150C
[Voltage Range]   3.3   3.135   3.465
|Junction Temperature
[Temperature Range]   27   150   -40
[Pullup Reference]   3.3   3.135   3.465
[Pulldown Reference]   0   0   -0
[Power Clamp Reference]   3.3   3.135   3.465
[GND Clamp Reference]   0   0   0
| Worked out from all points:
|   slope of the pulldown table from 0 to 0.495 V, typ, clamps not added: 17.2 ohm
|   slope of the pullup table from 0 to 0.495 V, typ, clamps not added: 22.7 ohm
|   GND clamp passes 1 mA (typ) near -0.60 V on its own axis
|   POWER clamp passes 1 mA (typ) near -0.67 V on its own axis
|   falling waveform, V_fixture 3.3V, R_fixture 250Ohm: 20-80 % time 453ps typ, 731ps min, 335ps max; typ from 3.3 V to 0.211 V
|   rising waveform, V_fixture 0V, R_fixture 250Ohm: 20-80 % time 453ps typ, 760ps min, 323ps max; typ from 0 V to 3.03 V
|   rising waveform, V_fixture 3.3V, R_fixture 250Ohm: 20-80 % time 1.9ns typ, 3.15ns min, 1.23ns max; typ from 0.211 V to 3.3 V
|   falling waveform, V_fixture 0V, R_fixture 250Ohm: 20-80 % time 1.58ns typ, 2.94ns min, 952ps max; typ from 3.03 V to 0 V
[Pulldown]
|   Voltage   I(typ)   I(min)   I(max)
-3.3V     -5.391mA   -2.637mA   -6.739mA
-1.34V    -9.008mA   -4.405mA   -11.57mA
-815.1mV  -23.22mA   -7.97mA    -44.63mA
-656.7mV  -36.04mA   -10.61mA   -43.07mA
-389.4mV  -22.93mA   -15.3mA    -27.14mA
2.65V     140.3mA    87.08mA    174.8mA
3.62V     174.4mA    98.85mA    229.4mA
4.036V    180.5mA    86.96mA    248.9mA
4.392V    167.1mA    69.64mA    256.5mA
4.788V    143mA      49mA       242.2mA
5.501V    94.87mA    12.32mA    198.1mA
6.6V      19.52mA    5.241mA    117.4mA
[GND Clamp]
|   Voltage   I(typ)   I(min)   I(max)
-3.3V     -2.041A    -2.068A    -2.04A
-1.32V    -391.8mA   -490.3mA   -343.8mA
-1.261V   -345.9mA   -446.1mA   -297mA
-1.181V   -286.2mA   -388.3mA   -236.3mA
-1.082V   -214.7mA   -318.1mA   -164mA
-894.3mV  -90.91mA   -193.7mA   -46.02mA
-815.1mV  -47.02mA   -145.7mA   -19.73mA
-745.8mV  -18.67mA   -106.2mA   -10.19mA
-607.2mV  -1.204mA   -39.07mA   -1.422mA
-498.3mV  -95.57uA   -8.536mA   -97.45uA
-339.9mV  -899.4nA   -220.9uA   -242.1nA
6.6V      0A         0A         0A
[Pullup]
|   Voltage   I(typ)   I(min)   I(max)
-3.3V     4.813mA    2.238mA    8.204mA
-2.062V   8.898mA    3.306mA    25.72mA
-815.1mV  32.97mA    15.17mA    41.92mA
2.788V    -104.4mA   -60.63mA   -139.4mA
3.561V    -118.3mA   -62.49mA   -168mA
3.907V    -120.2mA   -25.97mA   -177.7mA
4.046V    -104.7mA   -20.42mA   -180.1mA
4.264V    -46.1mA    -14.58mA   -169mA
4.343V    -39.21mA   -13.14mA   -151.1mA
4.551V    -28.02mA   -10.68mA   -65.58mA
4.828V    -20.67mA   -8.908mA   -38.04mA
6.6V      -11.96mA   -4.8mA     -19.97mA
[POWER Clamp]
|   Voltage   I(typ)   I(min)   I(max)
-3.3V     177.5mA    145.6mA    188.6mA
-1.27V    31.44mA    32.88mA    28.68mA
-1.201V   26.74mA    29.21mA    23.62mA
-1.132V   22.13mA    25.58mA    18.7mA
-1.112V   20.83mA    24.56mA    17.34mA
-953.7mV  10.95mA    16.49mA    7.865mA
-815.1mV  4.078mA    9.826mA    3.762mA
-745.8mV  2.162mA    6.753mA    2.431mA
-646.8mV  795.4uA    2.984mA    959.7uA
-528mV    111.9uA    465uA      111.1uA
-330mV    493.8nA    4.833uA    72.61nA
6.6V      0A         0A         0A
[Ramp]
R_load = 250
|   typ   min   max
dV/dt_r   1.81653/4.49675e-10   1.65467/7.54186e-10   1.939/3.21289e-10
dV/dt_f   1.8537/4.53083e-10   1.70903/7.27653e-10   1.96616/3.34543e-10
[Falling Waveform]
V_fixture = 3.3V
V_fixture_min = 3.135V
V_fixture_max = 3.465V
R_fixture = 250Ohm
C_fixture = 0F
|   Time   V(typ)   V(min)   V(max)
0s        3.3V       3.135V     3.465V
4.31ns    3.323V     3.135V     3.54V
4.942ns   3.333V     3.14V      648.5mV
5.416ns   3.341V     3.145V     228.2mV
6.19ns    3.234V     3.153V     204.1mV
6.926ns   650.1mV    3.161V     199.7mV
7.517ns   259.1mV    3.167V     197.5mV
9.958ns   219.2mV    3.134V     191.7mV
12.1ns    215.5mV    355.9mV    191.3mV
30ns      210.5mV    286.6mV    188.1mV
[Rising Waveform]
V_fixture = 0V
V_fixture_min = 0V
V_fixture_max = 0V
R_fixture = 250Ohm
C_fixture = 0F
|   Time   V(typ)   V(min)   V(max)
0s        864.5nV    11.55uV    -1.27uV
5.192ns   -41.6mV    93.26uV    -51.35mV
5.827ns   -49.38mV   103.3uV    2.763V
6.356ns   -49.99mV   -3.482mV   3.189V
7.161ns   84.86mV    -19.26mV   3.215V
7.889ns   2.567V     -33.54mV   3.217V
8.541ns   2.975V     -36.3mV    3.22V
10.97ns   3.016V     29.15mV    3.228V
13.2ns    3.022V     2.687V     3.228V
30ns      3.028V     2.758V     3.232V
[Rising Waveform]
V_fixture = 3.3V
V_fixture_min = 3.135V
V_fixture_max = 3.465V
R_fixture = 250Ohm
C_fixture = 0F
|   Time   V(typ)   V(min)   V(max)
0s        210.5mV    286.6mV    188.1mV
3.795ns   208mV      285.5mV    234.4mV
5.23ns    511.5mV    285.1mV    1.652V
5.68ns    978.8mV    285mV      3.139V
6.152ns   1.389V     284.8mV    3.425V
7.093ns   2.004V     333.3mV    3.451V
7.858ns   3.194V     797.4mV    3.453V
9.256ns   3.285V     1.835V     3.459V
12.19ns   3.296V     3.077V     3.462V
30ns      3.3V       3.135V     3.465V
[Falling Waveform]
|Gnd
V_fixture = 0V
V_fixture_min = 0V
V_fixture_max = 0V
R_fixture = 250Ohm
C_fixture = 0F
|   Time   V(typ)   V(min)   V(max)
0s        3.028V     2.758V     3.232V
3.311ns   3.026V     2.759V     3.085V
4.366ns   2.885V     2.76V      1.995V
4.819ns   2.546V     2.76V      311.5mV
5.222ns   2.141V     2.741V     33.92mV
6.166ns   1.439V     2.666V     12.24mV
6.677ns   285.4mV    2.585V     10.64mV
6.993ns   64.9mV     2.46V      9.648mV
11.31ns   3.775mV    45.48mV    2.919mV
30ns      865.2nV    11.46uV    -1.272uV
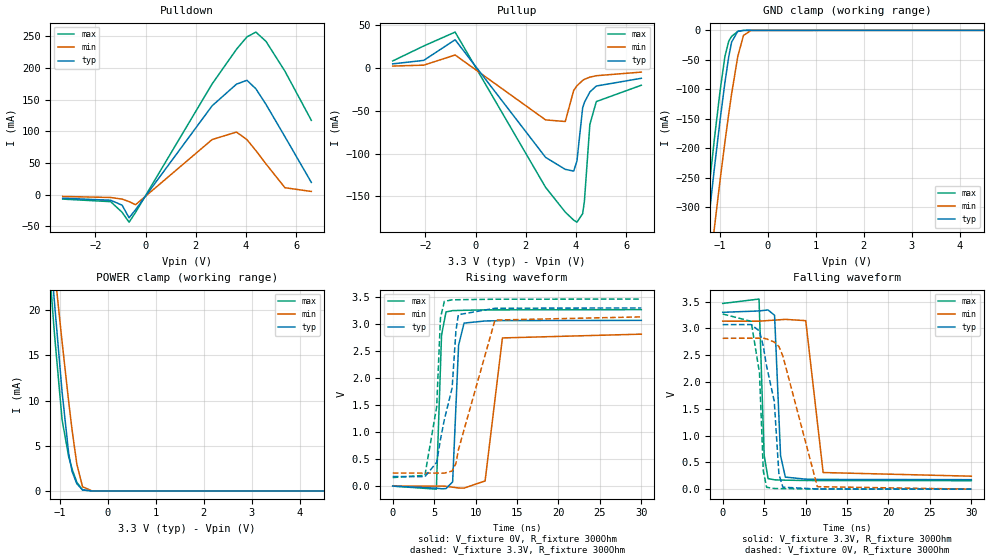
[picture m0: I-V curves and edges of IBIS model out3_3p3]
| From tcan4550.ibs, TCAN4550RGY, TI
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|   out3_3p3 Model
[Model]   out3_3p3
Model_type   3-state
Polarity   Non-Inverting
Vmeas = 1.65
Vref = 0
Cref = 2pF
Rref = 100000
|   typ   min   max
C_comp   6.601pF   6.247pF   6.755pF
|  Where Nom  PVT is Nominal Process, 3.3V,   27C
|   Fast PVT is Strong Process,  3.465, -40C
|   Slow PVT is Weak Process,   3.135V, 150C
[Voltage Range]   3.3   3.135   3.465
|Junction Temperature
[Temperature Range]   27   150   -40
[Pullup Reference]   3.3   3.135   3.465
[Pulldown Reference]   0   0   0
[Power Clamp Reference]   3.3   3.135   3.465
[GND Clamp Reference]   0   0   0
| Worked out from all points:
|   slope of the pulldown table from 0 to 0.495 V, typ, clamps not added: 17.2 ohm
|   slope of the pullup table from 0 to 0.495 V, typ, clamps not added: 22.7 ohm
|   GND clamp passes 1 mA (typ) near -0.61 V on its own axis
|   POWER clamp passes 1 mA (typ) near -0.67 V on its own axis
|   falling waveform, V_fixture 3.3V, R_fixture 300Ohm: 20-80 % time 444ps typ, 710ps min, 329ps max; typ from 3.3 V to 0.177 V
|   rising waveform, V_fixture 0V, R_fixture 300Ohm: 20-80 % time 442ps typ, 739ps min, 317ps max; typ from 0 V to 3.07 V
|   rising waveform, V_fixture 3.3V, R_fixture 300Ohm: 20-80 % time 1.85ns typ, 3.2ns min, 1.15ns max; typ from 0.177 V to 3.3 V
|   falling waveform, V_fixture 0V, R_fixture 300Ohm: 20-80 % time 1.51ns typ, 2.89ns min, 859ps max; typ from 3.07 V to 0 V
[Pulldown]
|   Voltage   I(typ)   I(min)   I(max)
-3.3V     -5.446mA   -2.657mA   -6.811mA
-1.389V   -8.611mA   -4.277mA   -10.89mA
-933.9mV  -16.45mA   -6.845mA   -27.65mA
-656.7mV  -36.33mA   -10.75mA   -43.24mA
-399.3mV  -23.51mA   -15.67mA   -27.83mA
2.65V     140.3mA    87.08mA    174.8mA
3.62V     174.4mA    98.85mA    229.4mA
4.036V    180.5mA    86.96mA    248.9mA
4.392V    167.1mA    69.64mA    256.5mA
4.798V    142.3mA    48.47mA    241.7mA
5.551V    91.43mA    11.09mA    194.7mA
6.6V      19.52mA    5.241mA    117.4mA
[GND Clamp]
|   Voltage   I(typ)   I(min)   I(max)
-3.3V     -2.034A    -2.059A    -2.035A
-1.31V    -380.7mA   -477.9mA   -333.5mA
-1.251V   -335.1mA   -434mA     -286.8mA
-1.112V   -232.6mA   -334.2mA   -182.9mA
-993.3mV  -150.8mA   -253mA     -101.3mA
-894.3mV  -88.38mA   -189.5mA   -44.09mA
-815.1mV  -44.84mA   -141.8mA   -18.28mA
-755.7mV  -20.05mA   -108.1mA   -10.34mA
-627mV    -1.568mA   -44.47mA   -1.84mA
-508.2mV  -106.4uA   -8.684mA   -113.2uA
-349.8mV  -1.081uA   -212uA     -345.4nA
6.6V      0A         0A         0A
[Pullup]
|   Voltage   I(typ)   I(min)   I(max)
-3.3V     4.813mA    2.238mA    8.204mA
-2.062V   8.898mA    3.306mA    25.72mA
-815.1mV  32.97mA    15.17mA    41.92mA
2.788V    -104.4mA   -60.63mA   -139.4mA
3.571V    -118.4mA   -62.52mA   -168.3mA
3.907V    -120.4mA   -26.21mA   -177.7mA
4.036V    -108.7mA   -20.86mA   -180.1mA
4.264V    -46.5mA    -14.55mA   -170.1mA
4.333V    -40.24mA   -13.27mA   -155.9mA
4.551V    -28.03mA   -10.68mA   -65.87mA
4.808V    -21.06mA   -9.026mA   -39.24mA
6.6V      -12.04mA   -4.8mA     -20.15mA
[POWER Clamp]
|   Voltage   I(typ)   I(min)   I(max)
-3.3V     177.5mA    145.6mA    188.6mA
-1.27V    31.44mA    32.88mA    28.68mA
-1.201V   26.74mA    29.21mA    23.62mA
-1.132V   22.13mA    25.58mA    18.7mA
-1.112V   20.83mA    24.56mA    17.34mA
-953.7mV  10.95mA    16.49mA    7.865mA
-815.1mV  4.078mA    9.826mA    3.762mA
-745.8mV  2.162mA    6.753mA    2.431mA
-646.8mV  795.4uA    2.984mA    959.7uA
-528mV    111.9uA    465uA      111.1uA
-330mV    496nA      4.833uA    74.52nA
6.6V      0A         0A         0A
[Ramp]
R_load = 300
|   typ   min   max
dV/dt_r   1.8421/4.3821e-10   1.68918/7.3222e-10   1.96112/3.14006e-10
dV/dt_f   1.87371/4.42423e-10   1.73575/7.06492e-10   1.98415/3.27945e-10
[Falling Waveform]
V_fixture = 3.3V
V_fixture_min = 3.135V
V_fixture_max = 3.465V
R_fixture = 300Ohm
C_fixture = 0F
|   Time   V(typ)   V(min)   V(max)
0s        3.3V       3.135V     3.465V
4.382ns   3.325V     3.134V     3.547V
5.003ns   3.336V     3.141V     629.7mV
5.47ns    3.344V     3.146V     197.7mV
6.259ns   3.244V     3.154V     174.3mV
6.982ns   624.1mV    3.162V     169.9mV
7.556ns   225.3mV    3.168V     167.8mV
10.02ns   186.5mV    3.144V     161.7mV
12.12ns   181.5mV    310.2mV    161.3mV
30ns      177.2mV    242.1mV    158.1mV
[Rising Waveform]
V_fixture = 0V
V_fixture_min = 0V
V_fixture_max = 0V
R_fixture = 300Ohm
C_fixture = 0F
|   Time   V(typ)   V(min)   V(max)
0s        938.3nV    12.87uV    220.1nV
5.267ns   -38.24mV   176.1uV    -56.79mV
5.892ns   -49.31mV   195.5uV    2.797V
6.432ns   -46.59mV   -3.9mV     3.227V
7.233ns   78.12mV    -20.38mV   3.251V
7.95ns    2.609V     -35.15mV   3.254V
8.61ns    3.02V      -37.24mV   3.257V
11.15ns   3.059V     95.43mV    3.265V
13.24ns   3.066V     2.745V     3.265V
30ns      3.07V      2.815V     3.269V
[Rising Waveform]
V_fixture = 3.3V
V_fixture_min = 3.135V
V_fixture_max = 3.465V
R_fixture = 300Ohm
C_fixture = 0F
|   Time   V(typ)   V(min)   V(max)
0s        177.2mV    242.1mV    158.1mV
3.886ns   174.2mV    240.9mV    199.9mV
5.306ns   441.1mV    240.5mV    1.471V
5.764ns   863.5mV    240.3mV    3.118V
6.237ns   1.235V     240.2mV    3.424V
7.167ns   1.816V     279.6mV    3.45V
7.63ns    2.877V     419.8mV    3.452V
7.92ns    3.175V     668.5mV    3.453V
12.34ns   3.295V     3.076V     3.462V
30ns      3.3V       3.135V     3.465V
[Falling Waveform]
|Gnd
V_fixture = 0V
V_fixture_min = 0V
V_fixture_max = 0V
R_fixture = 300Ohm
C_fixture = 0F
|   Time   V(typ)   V(min)   V(max)
0s        3.07V      2.815V     3.269V
3.425ns   3.071V     2.817V     3.132V
4.44ns    2.949V     2.817V     2.168V
4.896ns   2.665V     2.817V     340.9mV
5.3ns     2.293V     2.803V     34.34mV
6.222ns   1.639V     2.745V     12.64mV
6.783ns   279.8mV    2.663V     10.87mV
7.26ns    36.23mV    2.484V     9.356mV
11.42ns   4.05mV     46.1mV     2.932mV
30ns      217.6nV    12.87uV    -451.5nV
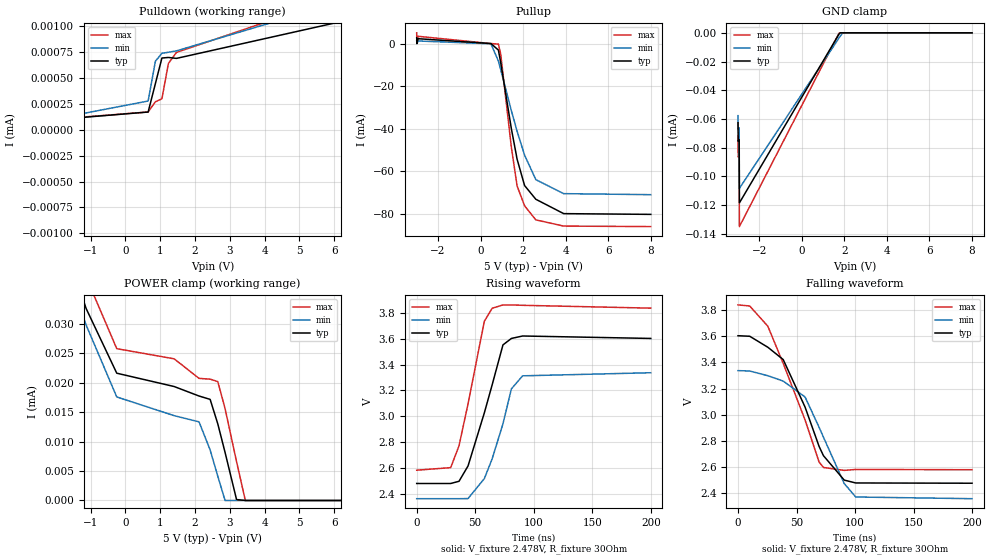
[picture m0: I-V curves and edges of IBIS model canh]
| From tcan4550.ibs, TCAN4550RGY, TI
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|   canh Model
[Model]   canh
Model_type   I/O
Polarity   Inverting
Enable   Active-Low
Vinl = 0.5
Vinh = 0.9
Vmeas = 3.05
Vref = 2.4776
Cref = 2pF
Rref = 30
|   typ   min   max
C_comp   12.068pF   11.367pF   12.813pF
|  Where Nom  PVT is Nominal Process, 5V,   27C
|   Fast PVT is Strong Process,  5.2V, -40C
|   Slow PVT is Weak Process,   4.8V, 150C
[Voltage Range]   5   4.8   5.2
|Junction Temperature
[Temperature Range]   27   150   -40
[Pullup Reference]   5   4.8   5.2
[Pulldown Reference]   0   0   0
[Power Clamp Reference]   5   4.8   5.2
[GND Clamp Reference]   0   0   0
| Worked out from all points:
|   slope of the pullup table from 0 to 0.75 V, typ, clamps not added: 1.34 kohm
|   POWER clamp passes 1 mA (typ) near -2.99 V on its own axis
|   falling waveform, V_fixture 2.478V, R_fixture 30Ohm: 20-80 % time 30.5ns typ, 30ns min, 31.9ns max; typ from 3.6 V to 2.48 V
|   rising waveform, V_fixture 2.478V, R_fixture 30Ohm: 20-80 % time 20.1ns typ, 19.1ns min, 16.8ns max; typ from 2.48 V to 3.6 V
[Pulldown]
|   Voltage   I(typ)   I(min)   I(max)
-3V       -290.5mA   -175.4mA   -461.5mA
-2.989V   -464.3nA   -2.405uA   43.59nA
-2.978V   -217.6nA   -720.6nA   52.22nA
-2.967V   -118nA     -384.2nA   58.43nA
-2.945V   -28.57nA   -156.2nA   66.75nA
-2.747V   76.62nA    57.73nA    81.99nA
652mV     170.6nA    276.6nA    171.1nA
861mV     445.1nA    660.6nA    269.2nA
1.048V    691.3nA    736.8nA    298.5nA
1.235V    696.7nA    747nA      639nA
1.466V    687.7nA    760.2nA    745.4nA
8V        1.178uA    1.412uA    1.49uA
[GND Clamp]
|   Voltage   I(typ)   I(min)   I(max)
-3V       -62.65uA   -57.73uA   -71.72uA
-2.989V   -75.6uA    -67.28uA   -86.52uA
-2.945V   -74.44uA   -66.24uA   -85.15uA
-2.934V   -118.5uA   -108.4uA   -135uA
1.752V    -782.2nA   -3.497uA   -163.9nA
1.796V    0A         -2.544uA   0A
1.928V    0A         0A         0A
8V        0A         0A         0A
[Pullup]
|   Voltage   I(typ)   I(min)   I(max)
-3V       2.766mA    1.317mA    5.042mA
-2.989V   1.1uA      1.188uA    1.421uA
-2.934V   2.278mA    1.204mA    3.399mA
487mV     806.6nA    -113.5uA   1.379uA
839mV     -3.06mA    -8.194mA   -258.7uA
949mV     -8.968mA   -12.32mA   -5.004mA
1.444V    -39.73mA   -31.35mA   -48.34mA
1.719V    -54.35mA   -41.24mA   -66.95mA
2.071V    -66.74mA   -52.45mA   -76.23mA
2.599V    -73.17mA   -63.95mA   -82.85mA
3.908V    -79.92mA   -70.53mA   -85.77mA
8V        -80.27mA   -71.01mA   -86.01mA
[POWER Clamp]
|   Voltage   I(typ)   I(min)   I(max)
-3V       422.8mA    271.8mA    597.3mA
-1.757V   43.71uA    40.25uA    48.48uA
-1.13V    32.56uA    29.76uA    37.9uA
-250mV    21.59uA    17.56uA    25.75uA
1.4V      19.33uA    14.39uA    24.03uA
2.115V    17.72uA    13.34uA    20.71uA
2.434V    17.15uA    8.573uA    20.58uA
2.654V    13uA       4.112uA    20.16uA
2.863V    8.153uA    0A         15.59uA
3.193V    161.6nA    0A         6.597uA
3.446V    0A         0A         0A
8V        0A         0A         0A
[Ramp]
R_load = 30
|   typ   min   max
dV/dt_r   0.675416/2.00801e-08   0.58619/1.89982e-08   0.754145/1.68171e-08
dV/dt_f   0.675416/3.04749e-08   0.58619/2.99191e-08   0.754152/3.17686e-08
[Falling Waveform]
V_fixture = 2.478V
V_fixture_min = 2.36V
V_fixture_max = 2.581V
R_fixture = 30Ohm
C_fixture = 0F
|   Time   V(typ)   V(min)   V(max)
0s        3.603V     3.337V     3.838V
10.02ns   3.599V     3.334V     3.83V
25.54ns   3.515V     3.298V     3.675V
38.65ns   3.421V     3.257V     3.392V
57.31ns   3.059V     3.136V     2.961V
69.33ns   2.758V     2.904V     2.639V
73.04ns   2.688V     2.829V     2.598V
90.75ns   2.502V     2.476V     2.576V
100.6ns   2.48V      2.373V     2.583V
200ns     2.478V     2.36V      2.581V
[Rising Waveform]
V_fixture = 2.478V
V_fixture_min = 2.36V
V_fixture_max = 2.581V
R_fixture = 30Ohm
C_fixture = 0F
|   Time   V(typ)   V(min)   V(max)
0s        2.478V     2.36V      2.581V
29.06ns   2.478V     2.36V      2.601V
36.15ns   2.495V     2.36V      2.77V
43.88ns   2.614V     2.361V     3.096V
57.81ns   3.026V     2.516V     3.736V
64.48ns   3.243V     2.669V     3.837V
73.71ns   3.553V     2.941V     3.863V
80.93ns   3.603V     3.212V     3.863V
90.51ns   3.622V     3.313V     3.86V
200ns     3.603V     3.337V     3.838V
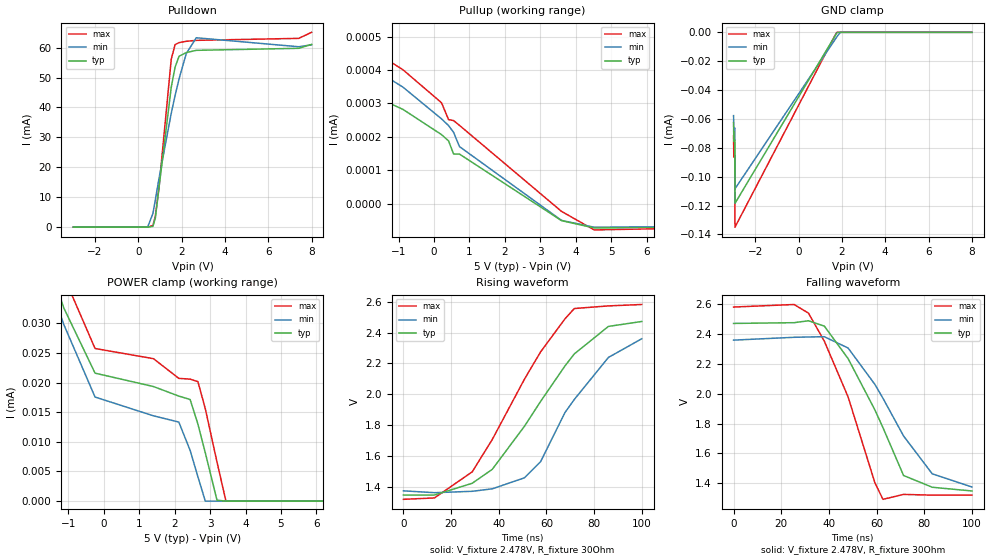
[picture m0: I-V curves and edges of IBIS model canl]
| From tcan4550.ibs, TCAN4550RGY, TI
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|   canl Model
[Model]   canl
Model_type   I/O
Polarity   Non-Inverting
Enable   Active-Low
Vinl = 0.5
Vinh = 0.9
Vmeas = 1.96
Vref = 2.4776
Cref = 2pF
Rref = 30
|   typ   min   max
C_comp   30.241pF   29.898pF   30.594pF
|  Where Nom  PVT is Nominal Process, 5V,   27C
|   Fast PVT is Strong Process,  5.2V, -40C
|   Slow PVT is Weak Process,   4.8V, 150C
[Voltage Range]   5   4.8   5.2
|Junction Temperature
[Temperature Range]   27   150   -40
[Pullup Reference]   5   4.8   5.2
[Pulldown Reference]   -0   -0   -0
[Power Clamp Reference]   5   4.8   5.2
[GND Clamp Reference]   0   0   0
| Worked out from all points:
|   slope of the pulldown table from 0 to 0.75 V, typ, clamps not added: 464 ohm
|   POWER clamp passes 1 mA (typ) near -2.99 V on its own axis
|   falling waveform, V_fixture 2.478V, R_fixture 30Ohm: 20-80 % time 19.9ns typ, 21.1ns min, 17.2ns max; typ from 2.47 V to 1.35 V
|   rising waveform, V_fixture 2.478V, R_fixture 30Ohm: 20-80 % time 30.6ns typ, 23.5ns min, 27.6ns max; typ from 1.35 V to 2.47 V
[Pulldown]
|   Voltage   I(typ)   I(min)   I(max)
-3V       -48.05pA   -622.7pA   -48.41pA
432mV     560.9nA    59.48uA    461.6nA
674mV     269.2uA    4.525mA    559.2uA
784mV     2.911mA    8.982mA    3.572mA
949mV     12.8mA     16.01mA    12.77mA
1.521V    46.74mA    38.06mA    56.09mA
1.697V    53.44mA    43.91mA    60.99mA
1.884V    57.13mA    49.62mA    61.68mA
2.214V    58.34mA    57.99mA    62.11mA
2.676V    59.09mA    63.29mA    62.43mA
7.406V    59.77mA    60.29mA    63.09mA
8V        61.07mA    60.93mA    65.11mA
[GND Clamp]
|   Voltage   I(typ)   I(min)   I(max)
-3V       -62.65uA   -57.73uA   -71.72uA
-2.989V   -75.6uA    -67.28uA   -86.52uA
-2.945V   -74.44uA   -66.24uA   -85.15uA
-2.934V   -118.5uA   -108.4uA   -135uA
1.752V    -782.2nA   -3.497uA   -163.9nA
1.796V    0A         -2.544uA   0A
1.928V    0A         0A         0A
8V        0A         0A         0A
[Pullup]
|   Voltage   I(typ)   I(min)   I(max)
-3V       422.7mA    271.8mA    597.3mA
-2.989V   595.3nA    1.492uA    703.7nA
-2.934V   413.7nA    538.3nA    568.2nA
-2.725V   372.1nA    470.8nA    524.9nA
-877mV    282.3nA    348.9nA    401nA
212mV     206.8nA    253.9nA    302.1nA
410mV     188nA      233.9nA    251.8nA
553mV     148.8nA    213.6nA    248.8nA
718mV     148.6nA    171nA      234.5nA
3.6V      -50.66nA   -50.01nA   -23.01nA
4.524V    -72.53nA   -70.48nA   -78.48nA
8V        -69.23nA   -67.4nA    -71.31nA
[POWER Clamp]
|   Voltage   I(typ)   I(min)   I(max)
-3V       422.8mA    271.8mA    597.3mA
-1.757V   43.71uA    40.25uA    48.48uA
-1.13V    32.56uA    29.76uA    37.9uA
-250mV    21.59uA    17.56uA    25.75uA
1.4V      19.33uA    14.39uA    24.03uA
2.115V    17.72uA    13.34uA    20.71uA
2.434V    17.15uA    8.573uA    20.58uA
2.654V    13uA       4.112uA    20.16uA
2.863V    8.153uA    0A         15.59uA
3.193V    161.6nA    0A         6.597uA
3.446V    0A         0A         0A
8V        0A         0A         0A
[Ramp]
R_load = 30
|   typ   min   max
dV/dt_r   0.674185/3.05247e-08   0.59127/2.34704e-08   0.757594/2.75074e-08
dV/dt_f   0.674191/1.98348e-08   0.59127/2.10131e-08   0.757597/1.71965e-08
[Falling Waveform]
V_fixture = 2.478V
V_fixture_min = 2.36V
V_fixture_max = 2.581V
R_fixture = 30Ohm
C_fixture = 0F
|   Time   V(typ)   V(min)   V(max)
0s        2.472V     2.36V      2.582V
25.39ns   2.477V     2.379V     2.599V
31.44ns   2.49V      2.381V     2.541V
38.09ns   2.454V     2.383V     2.353V
48.07ns   2.236V     2.307V     1.979V
59.31ns   1.892V     2.063V     1.403V
62.7ns    1.773V     1.97V      1.292V
71.34ns   1.452V     1.717V     1.325V
83.39ns   1.373V     1.463V     1.32V
100ns     1.348V     1.375V     1.32V
[Rising Waveform]
V_fixture = 2.478V
V_fixture_min = 2.36V
V_fixture_max = 2.581V
R_fixture = 30Ohm
C_fixture = 0F
|   Time   V(typ)   V(min)   V(max)
0s        1.348V     1.375V     1.32V
13.02ns   1.348V     1.363V     1.329V
28.86ns   1.424V     1.372V     1.498V
37.26ns   1.514V     1.388V     1.707V
50.74ns   1.792V     1.459V     2.097V
57.56ns   1.954V     1.564V     2.275V
67.79ns   2.184V     1.882V     2.489V
71.71ns   2.262V     1.967V     2.556V
86.02ns   2.44V      2.239V     2.573V
100ns     2.472V     2.36V      2.582V
